VERSION 5.7 ;
BUSBITCHARS "[]" ;
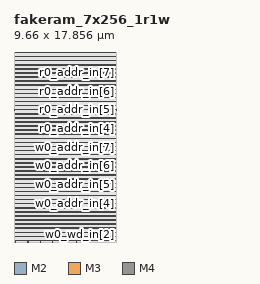
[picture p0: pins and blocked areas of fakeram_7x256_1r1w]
MACRO fakeram_7x256_1r1w
  FOREIGN fakeram_7x256_1r1w 0 0 ;
  SYMMETRY X Y R90 ;
  SIZE 9.660 BY 17.856 ;
  CLASS BLOCK ;
  PIN w0_wd_in[0]
    DIRECTION INPUT ;
    USE SIGNAL ;
    SHAPE ABUTMENT ;
    PORT
      LAYER M2 ;
      RECT 0.000 0.138 0.036 0.150 ;
    END
  END w0_wd_in[0]
  PIN w0_wd_in[1]
    DIRECTION INPUT ;
    USE SIGNAL ;
    SHAPE ABUTMENT ;
    PORT
      LAYER M2 ;
      RECT 0.000 1.890 0.036 1.902 ;
    END
  END w0_wd_in[1]
  PIN w0_wd_in[2]
    DIRECTION INPUT ;
    USE SIGNAL ;
    SHAPE ABUTMENT ;
    PORT
      LAYER M2 ;
      RECT 9.624 0.138 9.660 0.150 ;
    END
  END w0_wd_in[2]
  PIN w0_wd_in[3]
    DIRECTION INPUT ;
    USE SIGNAL ;
    SHAPE ABUTMENT ;
    PORT
      LAYER M2 ;
      RECT 9.624 1.890 9.660 1.902 ;
    END
  END w0_wd_in[3]
  PIN w0_wd_in[4]
    DIRECTION INPUT ;
    USE SIGNAL ;
    SHAPE ABUTMENT ;
    PORT
      LAYER M3 ;
      RECT 0.161 0.000 0.175 0.042 ;
    END
  END w0_wd_in[4]
  PIN w0_wd_in[5]
    DIRECTION INPUT ;
    USE SIGNAL ;
    SHAPE ABUTMENT ;
    PORT
      LAYER M3 ;
      RECT 1.309 0.000 1.323 0.042 ;
    END
  END w0_wd_in[5]
  PIN w0_wd_in[6]
    DIRECTION INPUT ;
    USE SIGNAL ;
    SHAPE ABUTMENT ;
    PORT
      LAYER M3 ;
      RECT 2.457 0.000 2.471 0.042 ;
    END
  END w0_wd_in[6]
  PIN r0_rd_out[0]
    DIRECTION OUTPUT ;
    USE SIGNAL ;
    SHAPE ABUTMENT ;
    PORT
      LAYER M3 ;
      RECT 3.605 0.000 3.619 0.042 ;
    END
  END r0_rd_out[0]
  PIN r0_rd_out[1]
    DIRECTION OUTPUT ;
    USE SIGNAL ;
    SHAPE ABUTMENT ;
    PORT
      LAYER M3 ;
      RECT 4.753 0.000 4.767 0.042 ;
    END
  END r0_rd_out[1]
  PIN r0_rd_out[2]
    DIRECTION OUTPUT ;
    USE SIGNAL ;
    SHAPE ABUTMENT ;
    PORT
      LAYER M3 ;
      RECT 5.901 0.000 5.915 0.042 ;
    END
  END r0_rd_out[2]
  PIN r0_rd_out[3]
    DIRECTION OUTPUT ;
    USE SIGNAL ;
    SHAPE ABUTMENT ;
    PORT
      LAYER M3 ;
      RECT 7.049 0.000 7.063 0.042 ;
    END
  END r0_rd_out[3]
  PIN r0_rd_out[4]
    DIRECTION OUTPUT ;
    USE SIGNAL ;
    SHAPE ABUTMENT ;
    PORT
      LAYER M3 ;
      RECT 0.161 17.814 0.175 17.856 ;
    END
  END r0_rd_out[4]
  PIN r0_rd_out[5]
    DIRECTION OUTPUT ;
    USE SIGNAL ;
    SHAPE ABUTMENT ;
    PORT
      LAYER M3 ;
      RECT 1.169 17.814 1.183 17.856 ;
    END
  END r0_rd_out[5]
  PIN r0_rd_out[6]
    DIRECTION OUTPUT ;
    USE SIGNAL ;
    SHAPE ABUTMENT ;
    PORT
      LAYER M3 ;
      RECT 2.177 17.814 2.191 17.856 ;
    END
  END r0_rd_out[6]
  PIN w0_addr_in[0]
    DIRECTION INPUT ;
    USE SIGNAL ;
    SHAPE ABUTMENT ;
    PORT
      LAYER M2 ;
      RECT 0.000 3.642 0.036 3.654 ;
    END
  END w0_addr_in[0]
  PIN w0_addr_in[1]
    DIRECTION INPUT ;
    USE SIGNAL ;
    SHAPE ABUTMENT ;
    PORT
      LAYER M2 ;
      RECT 0.000 5.394 0.036 5.406 ;
    END
  END w0_addr_in[1]
  PIN w0_addr_in[2]
    DIRECTION INPUT ;
    USE SIGNAL ;
    SHAPE ABUTMENT ;
    PORT
      LAYER M2 ;
      RECT 0.000 7.146 0.036 7.158 ;
    END
  END w0_addr_in[2]
  PIN w0_addr_in[3]
    DIRECTION INPUT ;
    USE SIGNAL ;
    SHAPE ABUTMENT ;
    PORT
      LAYER M2 ;
      RECT 0.000 8.898 0.036 8.910 ;
    END
  END w0_addr_in[3]
  PIN w0_addr_in[4]
    DIRECTION INPUT ;
    USE SIGNAL ;
    SHAPE ABUTMENT ;
    PORT
      LAYER M2 ;
      RECT 9.624 3.642 9.660 3.654 ;
    END
  END w0_addr_in[4]
  PIN w0_addr_in[5]
    DIRECTION INPUT ;
    USE SIGNAL ;
    SHAPE ABUTMENT ;
    PORT
      LAYER M2 ;
      RECT 9.624 5.394 9.660 5.406 ;
    END
  END w0_addr_in[5]
  PIN w0_addr_in[6]
    DIRECTION INPUT ;
    USE SIGNAL ;
    SHAPE ABUTMENT ;
    PORT
      LAYER M2 ;
      RECT 9.624 7.146 9.660 7.158 ;
    END
  END w0_addr_in[6]
  PIN w0_addr_in[7]
    DIRECTION INPUT ;
    USE SIGNAL ;
    SHAPE ABUTMENT ;
    PORT
      LAYER M2 ;
      RECT 9.624 8.898 9.660 8.910 ;
    END
  END w0_addr_in[7]
  PIN r0_addr_in[0]
    DIRECTION INPUT ;
    USE SIGNAL ;
    SHAPE ABUTMENT ;
    PORT
      LAYER M2 ;
      RECT 0.000 10.650 0.036 10.662 ;
    END
  END r0_addr_in[0]
  PIN r0_addr_in[1]
    DIRECTION INPUT ;
    USE SIGNAL ;
    SHAPE ABUTMENT ;
    PORT
      LAYER M2 ;
      RECT 0.000 12.402 0.036 12.414 ;
    END
  END r0_addr_in[1]
  PIN r0_addr_in[2]
    DIRECTION INPUT ;
    USE SIGNAL ;
    SHAPE ABUTMENT ;
    PORT
      LAYER M2 ;
      RECT 0.000 14.154 0.036 14.166 ;
    END
  END r0_addr_in[2]
  PIN r0_addr_in[3]
    DIRECTION INPUT ;
    USE SIGNAL ;
    SHAPE ABUTMENT ;
    PORT
      LAYER M2 ;
      RECT 0.000 15.906 0.036 15.918 ;
    END
  END r0_addr_in[3]
  PIN r0_addr_in[4]
    DIRECTION INPUT ;
    USE SIGNAL ;
    SHAPE ABUTMENT ;
    PORT
      LAYER M2 ;
      RECT 9.624 10.650 9.660 10.662 ;
    END
  END r0_addr_in[4]
  PIN r0_addr_in[5]
    DIRECTION INPUT ;
    USE SIGNAL ;
    SHAPE ABUTMENT ;
    PORT
      LAYER M2 ;
      RECT 9.624 12.402 9.660 12.414 ;
    END
  END r0_addr_in[5]
  PIN r0_addr_in[6]
    DIRECTION INPUT ;
    USE SIGNAL ;
    SHAPE ABUTMENT ;
    PORT
      LAYER M2 ;
      RECT 9.624 14.154 9.660 14.166 ;
    END
  END r0_addr_in[6]
  PIN r0_addr_in[7]
    DIRECTION INPUT ;
    USE SIGNAL ;
    SHAPE ABUTMENT ;
    PORT
      LAYER M2 ;
      RECT 9.624 15.906 9.660 15.918 ;
    END
  END r0_addr_in[7]
  PIN w0_we_in
    DIRECTION INPUT ;
    USE SIGNAL ;
    SHAPE ABUTMENT ;
    PORT
      LAYER M3 ;
      RECT 3.185 17.814 3.199 17.856 ;
    END
  END w0_we_in
  PIN w0_ce_in
    DIRECTION INPUT ;
    USE SIGNAL ;
    SHAPE ABUTMENT ;
    PORT
      LAYER M3 ;
      RECT 4.193 17.814 4.207 17.856 ;
    END
  END w0_ce_in
  PIN w0_clk
    DIRECTION INPUT ;
    USE SIGNAL ;
    SHAPE ABUTMENT ;
    PORT
      LAYER M3 ;
      RECT 5.201 17.814 5.215 17.856 ;
    END
  END w0_clk
  PIN r0_ce_in
    DIRECTION INPUT ;
    USE SIGNAL ;
    SHAPE ABUTMENT ;
    PORT
      LAYER M3 ;
      RECT 6.209 17.814 6.223 17.856 ;
    END
  END r0_ce_in
  PIN r0_clk
    DIRECTION INPUT ;
    USE SIGNAL ;
    SHAPE ABUTMENT ;
    PORT
      LAYER M3 ;
      RECT 7.217 17.814 7.231 17.856 ;
    END
  END r0_clk
  PIN VSS
    DIRECTION INOUT ;
    USE GROUND ;
    PORT
      LAYER M4 ;
      RECT 0.168 0.120 9.492 0.168 ;
      RECT 0.168 0.504 9.492 0.552 ;
      RECT 0.168 0.888 9.492 0.936 ;
      RECT 0.168 1.272 9.492 1.320 ;
      RECT 0.168 1.656 9.492 1.704 ;
      RECT 0.168 2.040 9.492 2.088 ;
      RECT 0.168 2.424 9.492 2.472 ;
      RECT 0.168 2.808 9.492 2.856 ;
      RECT 0.168 3.192 9.492 3.240 ;
      RECT 0.168 3.576 9.492 3.624 ;
      RECT 0.168 3.960 9.492 4.008 ;
      RECT 0.168 4.344 9.492 4.392 ;
      RECT 0.168 4.728 9.492 4.776 ;
      RECT 0.168 5.112 9.492 5.160 ;
      RECT 0.168 5.496 9.492 5.544 ;
      RECT 0.168 5.880 9.492 5.928 ;
      RECT 0.168 6.264 9.492 6.312 ;
      RECT 0.168 6.648 9.492 6.696 ;
      RECT 0.168 7.032 9.492 7.080 ;
      RECT 0.168 7.416 9.492 7.464 ;
      RECT 0.168 7.800 9.492 7.848 ;
      RECT 0.168 8.184 9.492 8.232 ;
      RECT 0.168 8.568 9.492 8.616 ;
      RECT 0.168 8.952 9.492 9.000 ;
      RECT 0.168 9.336 9.492 9.384 ;
      RECT 0.168 9.720 9.492 9.768 ;
      RECT 0.168 10.104 9.492 10.152 ;
      RECT 0.168 10.488 9.492 10.536 ;
      RECT 0.168 10.872 9.492 10.920 ;
      RECT 0.168 11.256 9.492 11.304 ;
      RECT 0.168 11.640 9.492 11.688 ;
      RECT 0.168 12.024 9.492 12.072 ;
      RECT 0.168 12.408 9.492 12.456 ;
      RECT 0.168 12.792 9.492 12.840 ;
      RECT 0.168 13.176 9.492 13.224 ;
      RECT 0.168 13.560 9.492 13.608 ;
      RECT 0.168 13.944 9.492 13.992 ;
      RECT 0.168 14.328 9.492 14.376 ;
      RECT 0.168 14.712 9.492 14.760 ;
      RECT 0.168 15.096 9.492 15.144 ;
      RECT 0.168 15.480 9.492 15.528 ;
      RECT 0.168 15.864 9.492 15.912 ;
      RECT 0.168 16.248 9.492 16.296 ;
      RECT 0.168 16.632 9.492 16.680 ;
      RECT 0.168 17.016 9.492 17.064 ;
      RECT 0.168 17.400 9.492 17.448 ;
      RECT 0.168 17.784 9.492 17.832 ;
    END
  END VSS
  PIN VDD
    DIRECTION INOUT ;
    USE POWER ;
    PORT
      LAYER M4 ;
      RECT 0.168 0.120 9.492 0.168 ;
      RECT 0.168 0.504 9.492 0.552 ;
      RECT 0.168 0.888 9.492 0.936 ;
      RECT 0.168 1.272 9.492 1.320 ;
      RECT 0.168 1.656 9.492 1.704 ;
      RECT 0.168 2.040 9.492 2.088 ;
      RECT 0.168 2.424 9.492 2.472 ;
      RECT 0.168 2.808 9.492 2.856 ;
      RECT 0.168 3.192 9.492 3.240 ;
      RECT 0.168 3.576 9.492 3.624 ;
      RECT 0.168 3.960 9.492 4.008 ;
      RECT 0.168 4.344 9.492 4.392 ;
      RECT 0.168 4.728 9.492 4.776 ;
      RECT 0.168 5.112 9.492 5.160 ;
      RECT 0.168 5.496 9.492 5.544 ;
      RECT 0.168 5.880 9.492 5.928 ;
      RECT 0.168 6.264 9.492 6.312 ;
      RECT 0.168 6.648 9.492 6.696 ;
      RECT 0.168 7.032 9.492 7.080 ;
      RECT 0.168 7.416 9.492 7.464 ;
      RECT 0.168 7.800 9.492 7.848 ;
      RECT 0.168 8.184 9.492 8.232 ;
      RECT 0.168 8.568 9.492 8.616 ;
      RECT 0.168 8.952 9.492 9.000 ;
      RECT 0.168 9.336 9.492 9.384 ;
      RECT 0.168 9.720 9.492 9.768 ;
      RECT 0.168 10.104 9.492 10.152 ;
      RECT 0.168 10.488 9.492 10.536 ;
      RECT 0.168 10.872 9.492 10.920 ;
      RECT 0.168 11.256 9.492 11.304 ;
      RECT 0.168 11.640 9.492 11.688 ;
      RECT 0.168 12.024 9.492 12.072 ;
      RECT 0.168 12.408 9.492 12.456 ;
      RECT 0.168 12.792 9.492 12.840 ;
      RECT 0.168 13.176 9.492 13.224 ;
      RECT 0.168 13.560 9.492 13.608 ;
      RECT 0.168 13.944 9.492 13.992 ;
      RECT 0.168 14.328 9.492 14.376 ;
      RECT 0.168 14.712 9.492 14.760 ;
      RECT 0.168 15.096 9.492 15.144 ;
      RECT 0.168 15.480 9.492 15.528 ;
      RECT 0.168 15.864 9.492 15.912 ;
      RECT 0.168 16.248 9.492 16.296 ;
      RECT 0.168 16.632 9.492 16.680 ;
      RECT 0.168 17.016 9.492 17.064 ;
      RECT 0.168 17.400 9.492 17.448 ;
      RECT 0.168 17.784 9.492 17.832 ;
    END
  END VDD
  OBS
    LAYER M1 ;
    RECT 0 0 9.660 17.856 ;
    LAYER M2 ;
    RECT 0 0 9.660 17.856 ;
    LAYER M3 ;
    RECT 0 0 9.660 17.856 ;
    LAYER M4 ;
    RECT 0 0 9.660 17.856 ;
  END
END fakeram_7x256_1r1w

END LIBRARY
